VERSION 5.7 ;
  NOWIREEXTENSIONATPIN ON ;
  DIVIDERCHAR "/" ;
  BUSBITCHARS "[]" ;
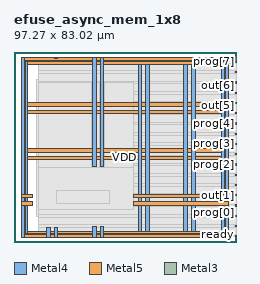
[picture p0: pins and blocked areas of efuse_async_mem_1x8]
MACRO efuse_async_mem_1x8
  CLASS BLOCK ;
  FOREIGN efuse_async_mem_1x8 ;
  ORIGIN 0.000 0.000 ;
  SIZE 97.270 BY 83.020 ;
  PIN VDD
    DIRECTION INOUT ;
    USE POWER ;
    PORT
      LAYER Metal4 ;
        RECT 4.880 3.560 6.080 78.760 ;
    END
    PORT
      LAYER Metal5 ;
        RECT 4.880 3.560 92.000 4.760 ;
    END
    PORT
      LAYER Metal5 ;
        RECT 4.880 77.560 92.000 78.760 ;
    END
    PORT
      LAYER Metal4 ;
        RECT 90.800 3.560 92.000 78.760 ;
    END
    PORT
      LAYER Metal4 ;
        RECT 14.280 1.860 15.880 6.440 ;
    END
    PORT
      LAYER Metal4 ;
        RECT 34.280 1.860 35.880 6.720 ;
    END
    PORT
      LAYER Metal4 ;
        RECT 34.280 32.810 35.880 80.460 ;
    END
    PORT
      LAYER Metal4 ;
        RECT 54.280 1.860 55.880 80.460 ;
    END
    PORT
      LAYER Metal4 ;
        RECT 74.280 1.860 75.880 80.460 ;
    END
    PORT
      LAYER Metal5 ;
        RECT 3.180 15.960 8.100 17.560 ;
    END
    PORT
      LAYER Metal5 ;
        RECT 3.180 35.960 93.700 37.560 ;
    END
    PORT
      LAYER Metal5 ;
        RECT 3.180 55.960 93.700 57.560 ;
    END
    PORT
      LAYER Metal5 ;
        RECT 52.280 15.960 93.700 17.560 ;
    END
  END VDD
  PIN VSS
    DIRECTION INOUT ;
    USE GROUND ;
    PORT
      LAYER Metal4 ;
        RECT 3.180 1.860 4.380 80.460 ;
    END
    PORT
      LAYER Metal5 ;
        RECT 3.180 1.860 93.700 3.060 ;
    END
    PORT
      LAYER Metal5 ;
        RECT 3.180 79.260 93.700 80.460 ;
    END
    PORT
      LAYER Metal4 ;
        RECT 92.500 1.860 93.700 80.460 ;
    END
    PORT
      LAYER Metal4 ;
        RECT 17.580 1.860 19.180 6.440 ;
    END
    PORT
      LAYER Metal4 ;
        RECT 17.580 80.020 19.180 80.460 ;
    END
    PORT
      LAYER Metal4 ;
        RECT 37.580 1.860 39.180 6.720 ;
    END
    PORT
      LAYER Metal4 ;
        RECT 37.580 32.810 39.180 80.460 ;
    END
    PORT
      LAYER Metal4 ;
        RECT 57.580 1.860 59.180 80.460 ;
    END
    PORT
      LAYER Metal4 ;
        RECT 77.580 1.860 79.180 80.460 ;
    END
    PORT
      LAYER Metal5 ;
        RECT 3.180 19.260 8.100 20.860 ;
    END
    PORT
      LAYER Metal5 ;
        RECT 3.180 39.260 93.700 40.860 ;
    END
    PORT
      LAYER Metal5 ;
        RECT 3.180 59.260 93.700 60.860 ;
    END
    PORT
      LAYER Metal5 ;
        RECT 52.280 19.260 93.700 20.860 ;
    END
  END VSS
  PIN out[0]
    DIRECTION OUTPUT ;
    USE SIGNAL ;
    ANTENNADIFFAREA 2.365600 ;
    PORT
      LAYER Metal3 ;
        RECT 96.710 11.200 97.270 11.760 ;
    END
  END out[0]
  PIN out[1]
    DIRECTION OUTPUT ;
    USE SIGNAL ;
    ANTENNADIFFAREA 2.365600 ;
    PORT
      LAYER Metal3 ;
        RECT 96.710 20.160 97.270 20.720 ;
    END
  END out[1]
  PIN out[2]
    DIRECTION OUTPUT ;
    USE SIGNAL ;
    ANTENNADIFFAREA 2.365600 ;
    PORT
      LAYER Metal3 ;
        RECT 96.710 29.120 97.270 29.680 ;
    END
  END out[2]
  PIN out[3]
    DIRECTION OUTPUT ;
    USE SIGNAL ;
    ANTENNADIFFAREA 2.365600 ;
    PORT
      LAYER Metal3 ;
        RECT 96.710 38.080 97.270 38.640 ;
    END
  END out[3]
  PIN out[4]
    DIRECTION OUTPUT ;
    USE SIGNAL ;
    ANTENNADIFFAREA 2.365600 ;
    PORT
      LAYER Metal3 ;
        RECT 96.710 47.040 97.270 47.600 ;
    END
  END out[4]
  PIN out[5]
    DIRECTION OUTPUT ;
    USE SIGNAL ;
    ANTENNADIFFAREA 2.365600 ;
    PORT
      LAYER Metal3 ;
        RECT 96.710 56.000 97.270 56.560 ;
    END
  END out[5]
  PIN out[6]
    DIRECTION OUTPUT ;
    USE SIGNAL ;
    ANTENNADIFFAREA 2.365600 ;
    PORT
      LAYER Metal3 ;
        RECT 96.710 64.960 97.270 65.520 ;
    END
  END out[6]
  PIN out[7]
    DIRECTION OUTPUT ;
    USE SIGNAL ;
    ANTENNADIFFAREA 2.365600 ;
    PORT
      LAYER Metal3 ;
        RECT 96.710 73.920 97.270 74.480 ;
    END
  END out[7]
  PIN prog[0]
    DIRECTION INPUT ;
    USE SIGNAL ;
    ANTENNAGATEAREA 2.114000 ;
    ANTENNADIFFAREA 0.410400 ;
    PORT
      LAYER Metal3 ;
        RECT 96.710 15.680 97.270 16.240 ;
    END
  END prog[0]
  PIN prog[1]
    DIRECTION INPUT ;
    USE SIGNAL ;
    ANTENNAGATEAREA 2.114000 ;
    ANTENNADIFFAREA 0.410400 ;
    PORT
      LAYER Metal3 ;
        RECT 96.710 24.640 97.270 25.200 ;
    END
  END prog[1]
  PIN prog[2]
    DIRECTION INPUT ;
    USE SIGNAL ;
    ANTENNAGATEAREA 2.114000 ;
    ANTENNADIFFAREA 0.410400 ;
    PORT
      LAYER Metal3 ;
        RECT 96.710 33.600 97.270 34.160 ;
    END
  END prog[2]
  PIN prog[3]
    DIRECTION INPUT ;
    USE SIGNAL ;
    ANTENNAGATEAREA 2.114000 ;
    ANTENNADIFFAREA 0.410400 ;
    PORT
      LAYER Metal3 ;
        RECT 96.710 42.560 97.270 43.120 ;
    END
  END prog[3]
  PIN prog[4]
    DIRECTION INPUT ;
    USE SIGNAL ;
    ANTENNAGATEAREA 2.114000 ;
    ANTENNADIFFAREA 0.410400 ;
    PORT
      LAYER Metal3 ;
        RECT 96.710 51.520 97.270 52.080 ;
    END
  END prog[4]
  PIN prog[5]
    DIRECTION INPUT ;
    USE SIGNAL ;
    ANTENNAGATEAREA 2.114000 ;
    ANTENNADIFFAREA 0.410400 ;
    PORT
      LAYER Metal3 ;
        RECT 96.710 60.480 97.270 61.040 ;
    END
  END prog[5]
  PIN prog[6]
    DIRECTION INPUT ;
    USE SIGNAL ;
    ANTENNAGATEAREA 2.114000 ;
    ANTENNADIFFAREA 0.410400 ;
    PORT
      LAYER Metal3 ;
        RECT 96.710 69.440 97.270 70.000 ;
    END
  END prog[6]
  PIN prog[7]
    DIRECTION INPUT ;
    USE SIGNAL ;
    ANTENNAGATEAREA 2.114000 ;
    ANTENNADIFFAREA 0.410400 ;
    PORT
      LAYER Metal3 ;
        RECT 96.710 78.400 97.270 78.960 ;
    END
  END prog[7]
  PIN ready
    DIRECTION OUTPUT ;
    USE SIGNAL ;
    ANTENNADIFFAREA 4.731200 ;
    PORT
      LAYER Metal3 ;
        RECT 96.710 2.240 97.270 2.800 ;
    END
  END ready
  PIN reset_n
    DIRECTION INPUT ;
    USE SIGNAL ;
    ANTENNAGATEAREA 19.511999 ;
    ANTENNADIFFAREA 4.104000 ;
    PORT
      LAYER Metal3 ;
        RECT 96.710 6.720 97.270 7.280 ;
    END
  END reset_n
  OBS
      LAYER Nwell ;
        RECT 10.020 11.330 87.230 70.990 ;
      LAYER Metal1 ;
        RECT 10.610 11.460 86.800 70.860 ;
      LAYER Metal2 ;
        RECT 10.610 2.330 91.700 78.870 ;
      LAYER Metal3 ;
        RECT 10.800 78.100 96.410 78.820 ;
        RECT 10.800 74.780 97.130 78.100 ;
        RECT 10.800 73.620 96.410 74.780 ;
        RECT 10.800 70.300 97.130 73.620 ;
        RECT 10.800 69.140 96.410 70.300 ;
        RECT 10.800 65.820 97.130 69.140 ;
        RECT 10.800 64.660 96.410 65.820 ;
        RECT 10.800 61.340 97.130 64.660 ;
        RECT 10.800 60.180 96.410 61.340 ;
        RECT 10.800 56.860 97.130 60.180 ;
        RECT 10.800 55.700 96.410 56.860 ;
        RECT 10.800 52.380 97.130 55.700 ;
        RECT 10.800 51.220 96.410 52.380 ;
        RECT 10.800 47.900 97.130 51.220 ;
        RECT 10.800 46.740 96.410 47.900 ;
        RECT 10.800 43.420 97.130 46.740 ;
        RECT 10.800 42.260 96.410 43.420 ;
        RECT 10.800 38.940 97.130 42.260 ;
        RECT 10.800 37.780 96.410 38.940 ;
        RECT 10.800 34.460 97.130 37.780 ;
        RECT 10.800 33.300 96.410 34.460 ;
        RECT 10.800 29.980 97.130 33.300 ;
        RECT 10.800 28.820 96.410 29.980 ;
        RECT 10.800 25.500 97.130 28.820 ;
        RECT 10.800 24.340 96.410 25.500 ;
        RECT 10.800 21.020 97.130 24.340 ;
        RECT 10.800 19.860 96.410 21.020 ;
        RECT 10.800 16.540 97.130 19.860 ;
        RECT 10.800 15.380 96.410 16.540 ;
        RECT 10.800 12.060 97.130 15.380 ;
        RECT 10.800 10.900 96.410 12.060 ;
        RECT 10.800 7.580 97.130 10.900 ;
        RECT 10.800 6.420 96.410 7.580 ;
        RECT 10.800 3.100 97.130 6.420 ;
        RECT 10.800 2.380 96.410 3.100 ;
      LAYER Metal4 ;
        RECT 10.610 32.510 33.980 69.910 ;
        RECT 36.180 32.510 37.280 69.910 ;
        RECT 39.480 32.510 52.290 69.910 ;
        RECT 10.610 14.090 52.290 32.510 ;
      LAYER Metal5 ;
        RECT 18.580 17.000 41.840 22.530 ;
  END
END efuse_async_mem_1x8
END LIBRARY

